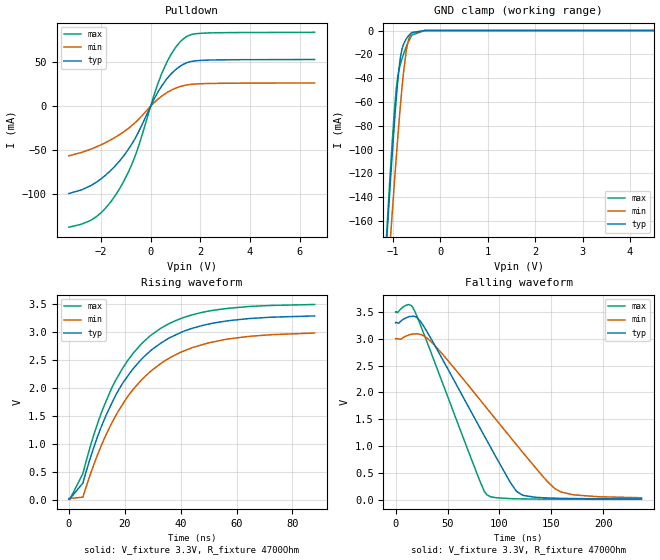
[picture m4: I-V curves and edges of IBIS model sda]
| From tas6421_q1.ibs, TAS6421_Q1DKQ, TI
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|   sda Model
[Model]   sda
Model_type   I/O_open_drain
Polarity   Non-Inverting
Vinl = 0.99
Vinh = 2.31
Vmeas = 1.65
Vref = 3.3
Cref = 2pF
Rref = 4700
|   typ   min   max
|   (nom PVT)   (fast PVT)   (slow PVT)
C_comp   1.956e-12   1.803e-12   2.012e-12
| Where nom  PVT is Nominal Process, 3.3V, 27C
|   Fast PVT is Strong Process,  3.5V, -40C
|   Slow PVT is Weak Process,   3V, 150C
[Model spec]
|subparameter
Vinl   0.99   0.90   1.05
Vinh   2.31   2.10   2.45
[Voltage Range]   3.3   3   3.5
|Junction Temperature
[Temperature Range]   27   150   -40
[Pullup Reference]   3.3   3   3.5
[Pulldown Reference]   0   0   0
[Power Clamp Reference]   3.3   3   3.5
[GND Clamp Reference]   0   0   0
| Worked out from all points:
|   slope of the pulldown table from 0 to 0.495 V, typ, clamps not added: 19.9 ohm
|   falling waveform, V_fixture 3.3V, R_fixture 4700Ohm: 20-80 % time 55.9ns typ, 75ns min, 41.1ns max; typ from 3.3 V to 0.016 V
|   rising waveform, V_fixture 3.3V, R_fixture 4700Ohm: 20-80 % time 21.3ns typ, 22.8ns min, 19.9ns max; typ from 0.012 V to 3.29 V
[Pulldown]
|   Voltage   I(typ)   I(min)   I(max)
-3.3V     -99.17mA   -56.36mA   -137.3mA
-2.187V   -86.26mA   -46.17mA   -125.4mA
-1.653V   -74.09mA   -38.9mA    -110.1mA
-1.267V   -62.56mA   -32.47mA   -94.28mA
-914.1mV  -49.53mA   -25.48mA   -75.62mA
-615mV    -35.89mA   -18.39mA   -55.51mA
141mV     8.345mA    4.125mA    13.44mA
462.5mV   23.86mA    11.81mA    38.32mA
858mV     37.74mA    18.62mA    60.61mA
1.341V    47.93mA    23.46mA    77.07mA
2.041V    52.03mA    25.53mA    82.82mA
6.6V      52.99mA    26.37mA    83.85mA
[GND Clamp]
|   Voltage   I(typ)   I(min)   I(max)
-3.3V     -1.775A    -1.719A    -1.841A
-1.13V    -175.7mA   -220.7mA   -169.6mA
-1.056V   -129mA     -177.2mA   -119.8mA
-1.026V   -111mA     -160.1mA   -100.8mA
-927mV    -56.11mA   -105.5mA   -48.12mA
-851.4mV  -25.44mA   -67.54mA   -29.68mA
-780mV    -11.99mA   -36.69mA   -20.21mA
-717mV    -6.878mA   -16.61mA   -13.39mA
-666mV    -4.086mA   -7.158mA   -8.704mA
-594.5mV  -1.595mA   -2.044mA   -3.733mA
-330mV    -7.451uA   -31.37uA   -5.074uA
6.6V      0A         0A         0A
[POWER Clamp]
|   Voltage   I(typ)   I(min)   I(max)
-3.3V     0A         0A         0A
0V        0A         0A         0A
6.6V      0A         0A         0A
[Ramp]
R_load = 4700
|   typ   min   max
dV/dt_r   1.97304/2.15244e-08   1.78711/2.31201e-08   2.09541/1.99936e-08
dV/dt_f   1.97191/5.58691e-08   1.78233/7.52238e-08   2.09515/4.1067e-08
[Falling Waveform]
V_fixture = 3.3V
V_fixture_min = 3V
V_fixture_max = 3.5V
R_fixture = 4700Ohm
|   Time   V(typ)   V(min)   V(max)
0s        3.3V       3V         3.5V
12.24ns   3.404V     3.065V     3.636V
17.68ns   3.416V     3.088V     3.538V
36.09ns   2.93V      2.905V     2.638V
80ns      1.381V     1.892V     404.2mV
87.93ns   1.102V     1.702V     92.68mV
110.5ns   321.6mV    1.165V     21.71mV
122.5ns   84.68mV    881.6mV    16.77mV
159.5ns   27.16mV    144.9mV    11.35mV
236.8ns   15.65mV    38.4mV     8.697mV
[Rising Waveform]
V_fixture = 3.3V
V_fixture_min = 3V
V_fixture_max = 3.5V
R_fixture = 4700Ohm
|   Time   V(typ)   V(min)   V(max)
0s        11.52mV    21.15mV    7.585mV
5.031ns   296.6mV    44.48mV    465.6mV
10.49ns   1.156V     828.4mV    1.393V
15.83ns   1.771V     1.413V     2.046V
21.79ns   2.263V     1.895V     2.539V
29.02ns   2.655V     2.285V     2.927V
38.48ns   2.953V     2.599V     3.21V
50.02ns   3.141V     2.806V     3.374V
65.06ns   3.243V     2.924V     3.458V
87.93ns   3.288V     2.981V     3.492V
